VERSION 5.7 ;
BUSBITCHARS "[]" ;
DIVIDERCHAR "/" ;

PROPERTYDEFINITIONS
  LAYER LEF58_TYPE STRING ;
END PROPERTYDEFINITIONS

MANUFACTURINGGRID 0.05 ;

LAYER OVERLAP
  TYPE OVERLAP ;
END OVERLAP

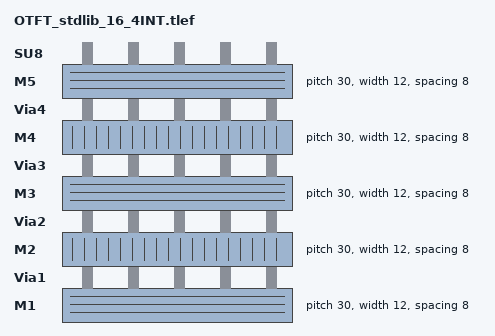
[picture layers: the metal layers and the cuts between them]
LAYER M1
  TYPE ROUTING ;
  DIRECTION HORIZONTAL ;
  PITCH 30 30 ;
  WIDTH 12 ;
  OFFSET 15 15 ;
  SPACING 8 ;
END M1

LAYER Via1
  TYPE CUT ;
END Via1

LAYER M2
  TYPE ROUTING ;
  DIRECTION VERTICAL ;
  PITCH 30 30 ;
  WIDTH 12 ;
  OFFSET 15 15 ;
  SPACING 8 ;
END M2

LAYER Via2
  TYPE CUT ;
END Via2

LAYER M3
  TYPE ROUTING ;
  DIRECTION HORIZONTAL ;
  PITCH 30 30 ;
  WIDTH 12 ;
  OFFSET 15 15 ;
  SPACING 8 ;
END M3

LAYER Via3
  TYPE CUT ;
END Via3

LAYER M4
  TYPE ROUTING ;
  DIRECTION VERTICAL ;
  PITCH 30 30 ;
  WIDTH 12 ;
  OFFSET 15 15 ;
  SPACING 8 ;
END M4

LAYER Via4
  TYPE CUT ;
END Via4

LAYER M5
  TYPE ROUTING ;
  DIRECTION HORIZONTAL ;
  PITCH 30 30 ;
  WIDTH 12 ;
  OFFSET 15 15 ;
  SPACING 8 ;
END M5

LAYER SU8
  TYPE CUT ;
  PROPERTY LEF58_TYPE "TYPE PASSIVATION ;" ;
END SU8

VIARULE M2_M1 GENERATE DEFAULT
  LAYER M1 ;
    ENCLOSURE 5 5 ;
  LAYER M2 ;
    ENCLOSURE 5 5 ;
  LAYER Via1 ;
    RECT -2.5 -2.5 2.5 2.5 ;
    SPACING 10 BY 10 ;
    RESISTANCE 5.000000 ;
END M2_M1

VIARULE M3_M2 GENERATE DEFAULT
  LAYER M2 ;
    ENCLOSURE 5 5 ;
  LAYER M3 ;
    ENCLOSURE 5 5 ;
  LAYER Via2 ;
    RECT -2.5 -2.5 2.5 2.5 ;
    SPACING 10 BY 10 ;
    RESISTANCE 5.000000 ;
END M3_M2

VIARULE M4_M3 GENERATE DEFAULT
  LAYER M3 ;
    ENCLOSURE 5 5 ;
  LAYER M4 ;
    ENCLOSURE 5 5 ;
  LAYER Via3 ;
    RECT -2.5 -2.5 2.5 2.5 ;
    SPACING 10 BY 10 ;
    RESISTANCE 5.000000 ;
END M4_M3

VIARULE M5_M4 GENERATE DEFAULT
  LAYER M4 ;
    ENCLOSURE 5 5 ;
  LAYER M5 ;
    ENCLOSURE 5 5 ;
  LAYER Via4 ;
    RECT -2.5 -2.5 2.5 2.5 ;
    SPACING 10 BY 10 ;
    RESISTANCE 5.000000 ;
END M5_M4

NONDEFAULTRULE virtuosoDefaultSetup
  LAYER M1
    WIDTH 12 ;
  END M1
  LAYER M2
    WIDTH 12 ;
  END M2
  LAYER M3
    WIDTH 12 ;
  END M3
  LAYER M4
    WIDTH 12 ;
  END M4
  LAYER M5
    WIDTH 12 ;
  END M5
  USEVIARULE M2_M1 ;
  USEVIARULE M2_MC ;
  USEVIARULE M3_M2 ;
  USEVIARULE M4_M3 ;
  USEVIARULE M5_M4 ;
END virtuosoDefaultSetup

NONDEFAULTRULE virtuosoDefaultExtractorSetup
  LAYER M1
    WIDTH 12 ;
  END M1
  LAYER M2
    WIDTH 12 ;
  END M2
  LAYER M3
    WIDTH 12 ;
  END M3
  LAYER M4
    WIDTH 12 ;
  END M4
  LAYER M5
    WIDTH 12 ;
  END M5
  USEVIARULE M2_M1 ;
  USEVIARULE M2_MC ;
  USEVIARULE M3_M2 ;
  USEVIARULE M4_M3 ;
  USEVIARULE M5_M4 ;
END virtuosoDefaultExtractorSetup

SITE CoreSite
  CLASS CORE ;
  SYMMETRY Y ;
  SIZE 10 BY 900 ;
END CoreSite

END LIBRARY
